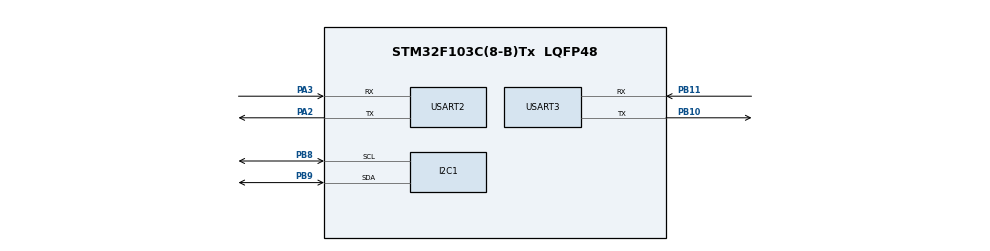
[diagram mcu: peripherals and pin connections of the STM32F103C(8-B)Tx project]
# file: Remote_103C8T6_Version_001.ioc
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Mcu.Family=STM32F1
Mcu.Name=STM32F103C(8-B)Tx
Mcu.Package=LQFP48
NVIC.PriorityGroup=NVIC_PRIORITYGROUP_4
NVIC.USART3_IRQn=true\:0\:0\:false\:false\:true\:true\:true\:true
PA13.Mode=Serial_Wire
PA13.Signal=SYS_JTMS-SWDIO
PA14.Mode=Serial_Wire
PA14.Signal=SYS_JTCK-SWCLK
PA2.Mode=Asynchronous
PA2.Signal=USART2_TX
PA3.Mode=Asynchronous
PA3.Signal=USART2_RX
PB10.Mode=Asynchronous
PB10.Signal=USART3_TX
PB11.Mode=Asynchronous
PB11.Signal=USART3_RX
PB8.Mode=I2C
PB8.Signal=I2C1_SCL
PB9.Mode=I2C
PB9.Signal=I2C1_SDA
PC14-OSC32_IN.Mode=LSE-External-Oscillator
PC14-OSC32_IN.Signal=RCC_OSC32_IN
PC15-OSC32_OUT.Mode=LSE-External-Oscillator
PC15-OSC32_OUT.Signal=RCC_OSC32_OUT
PD0-OSC_IN.Mode=HSE-External-Oscillator
PD0-OSC_IN.Signal=RCC_OSC_IN
PD1-OSC_OUT.Mode=HSE-External-Oscillator
PD1-OSC_OUT.Signal=RCC_OSC_OUT
ProjectManager.HeapSize=0x200
ProjectManager.StackSize=0x400
ProjectManager.TargetToolchain=STM32CubeIDE
RCC.APB1Freq_Value=8000000
RCC.APB2Freq_Value=8000000
USART2.VirtualMode=VM_ASYNC
USART3.VirtualMode=VM_ASYNC
board=custom

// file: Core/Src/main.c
/* USER CODE BEGIN Header */
/**
 ******************************************************************************
 * @file           : main.c
 * @brief          : Main program body
 ******************************************************************************
 * @attention
 *
 * Copyright (c) 2025 STMicroelectronics.
 * All rights reserved.
 *
 * This software is licensed under terms that can be found in the LICENSE file
 * in the root directory of this software component.
 * If no LICENSE file comes with this software, it is provided AS-IS.
 *
 ******************************************************************************
 */
/* USER CODE END Header */
#include "main.h"

/* USER CODE BEGIN Includes */
#include<string.h>
#include<stdio.h>
#include "stm32f1xx_hal.h"
#include "stm32f1xx_hal_gpio_ex.h"
#include "stm32f1xx_hal_rcc_ex.h"
#include <stdint.h>
#include <stdlib.h>
#include"ssd1306.h"

/* USER CODE END Includes */

I2C_HandleTypeDef hi2c1;

UART_HandleTypeDef huart2;
UART_HandleTypeDef huart3;

/* USER CODE BEGIN PV */
#define RBUF_SIZE 256
volatile uint8_t rbuf[RBUF_SIZE];
volatile uint16_t rhead = 0, rtail = 0;

uint8_t rx3_byte;
uint8_t c;
char line[32];
uint8_t idx = 0;
/* USER CODE END PV */

void SystemClock_Config(void);
static void MX_GPIO_Init(void);
static void MX_USART2_UART_Init(void);
static void MX_USART3_UART_Init(void);
static void MX_I2C1_Init(void);

/* USER CODE BEGIN 0 */
static inline void rbuf_push_isr(uint8_t b) {
	uint16_t next = (rhead + 1) & (RBUF_SIZE - 1);
	if (next != rtail) {
		rbuf[rhead] = b;
		rhead = next;
	}
}

/* -------- Pop Byte from Ring Buffer -------- */
static inline int rbuf_pop(uint8_t *out) {
	__disable_irq();
	if (rtail == rhead) {
		__enable_irq();
		return 0;
	}
	*out = rbuf[rtail];
	rtail = (rtail + 1) & (RBUF_SIZE - 1);
	__enable_irq();
	return 1;
}

/* -------- UART RX ISR -------- */
void HAL_UART_RxCpltCallback(UART_HandleTypeDef *huart) {
	if (huart->Instance == USART3) {
		rbuf_push_isr(rx3_byte);
		HAL_UART_Receive_IT(&huart3, &rx3_byte, 1);
	}
}

/* -------- UART error handle -------- */
void HAL_UART_ErrorCallback(UART_HandleTypeDef *huart) {
	if (huart->Instance == USART3) {
		__HAL_UART_CLEAR_OREFLAG(huart);
		HAL_UART_Receive_IT(&huart3, &rx3_byte, 1);
	}
}

void UART3_SendString(char *s) {
	HAL_UART_Transmit(&huart3, (uint8_t*) s, strlen(s), HAL_MAX_DELAY);
}
/* USER CODE END 0 */

int main(void)
{

  /* MCU Configuration--------------------------------------------------------*/

  /* Reset of all peripherals, Initializes the Flash interface and the Systick. */
  HAL_Init();

  /* USER CODE BEGIN Init */
	__HAL_RCC_AFIO_CLK_ENABLE();           // IMPORTANT
	// PB10/PB11 used
  /* USER CODE END Init */

  /* Configure the system clock */
  SystemClock_Config();

  /* Initialize all configured peripherals */
  MX_GPIO_Init();
  MX_USART2_UART_Init();
  MX_USART3_UART_Init();
  MX_I2C1_Init();
  /* USER CODE BEGIN 2 */
	HAL_UART_Receive_IT(&huart3, &rx3_byte, 1);

	/* ---- OLED ---- */
	SSD1306_Init();
	SSD1306_Clear();
	SSD1306_Update();

	/* ---- Start Msg ---- */
	char startMsg[] = "STM32 UART3 Ready\r\n";
	HAL_UART_Transmit(&huart2, (uint8_t*) startMsg, strlen(startMsg),
	HAL_MAX_DELAY);

	uint8_t c;
	static char line[64];
	static uint8_t idx = 0;
  /* USER CODE END 2 */

  /* Infinite loop */
	while (1) {

    /* USER CODE BEGIN 3 */
		while (rbuf_pop(&c)) {

			if (c == '\n') {

				line[idx] = '\0';
				idx = 0;

				/* ---------- Process BTN:x ---------- */
				if (strncmp(line, "BTN:", 4) == 0) {

					int btn = atoi(&line[4]);

					char msg[40];
					sprintf(msg, "Button %d Pressed\r\n", btn);

					/* Send back to ESP32 */
					UART3_SendString(msg);

					/* Print on UART2 (PC) */
					HAL_UART_Transmit(&huart2, (uint8_t*) msg, strlen(msg),
					HAL_MAX_DELAY);

					/* -------- OLED Output -------- */
					SSD1306_Clear();
					SSD1306_WriteStringXY(0, 0, "BUTTON PRESSED:");
					char oledMsg[20];
					sprintf(oledMsg, "%d", btn);
					SSD1306_WriteStringXY(0, 20, oledMsg);
					SSD1306_Update();
				}
			} else if (c != '\r') {
				if (idx < sizeof(line) - 1)
					line[idx++] = c;
			}
		}

		HAL_Delay(1);

	}
  /* USER CODE END 3 */
}

void SystemClock_Config(void)
{
  RCC_OscInitTypeDef RCC_OscInitStruct = {0};
  RCC_ClkInitTypeDef RCC_ClkInitStruct = {0};

  /** Initializes the RCC Oscillators according to the specified parameters
  * in the RCC_OscInitTypeDef structure.
  */
  RCC_OscInitStruct.OscillatorType = RCC_OSCILLATORTYPE_HSE;
  RCC_OscInitStruct.HSEState = RCC_HSE_ON;
  RCC_OscInitStruct.HSEPredivValue = RCC_HSE_PREDIV_DIV1;
  RCC_OscInitStruct.HSIState = RCC_HSI_ON;
  RCC_OscInitStruct.PLL.PLLState = RCC_PLL_ON;
  RCC_OscInitStruct.PLL.PLLSource = RCC_PLLSOURCE_HSE;
  RCC_OscInitStruct.PLL.PLLMUL = RCC_PLL_MUL9;
  if (HAL_RCC_OscConfig(&RCC_OscInitStruct) != HAL_OK)
  {
    Error_Handler();
  }

  /** Initializes the CPU, AHB and APB buses clocks
  */
  RCC_ClkInitStruct.ClockType = RCC_CLOCKTYPE_HCLK|RCC_CLOCKTYPE_SYSCLK
                              |RCC_CLOCKTYPE_PCLK1|RCC_CLOCKTYPE_PCLK2;
  RCC_ClkInitStruct.SYSCLKSource = RCC_SYSCLKSOURCE_PLLCLK;
  RCC_ClkInitStruct.AHBCLKDivider = RCC_SYSCLK_DIV2;
  RCC_ClkInitStruct.APB1CLKDivider = RCC_HCLK_DIV2;
  RCC_ClkInitStruct.APB2CLKDivider = RCC_HCLK_DIV1;

  if (HAL_RCC_ClockConfig(&RCC_ClkInitStruct, FLASH_LATENCY_2) != HAL_OK)
  {
    Error_Handler();
  }
}

static void MX_I2C1_Init(void)
{

  hi2c1.Instance = I2C1;
  hi2c1.Init.ClockSpeed = 100000;
  hi2c1.Init.DutyCycle = I2C_DUTYCYCLE_2;
  hi2c1.Init.OwnAddress1 = 0;
  hi2c1.Init.AddressingMode = I2C_ADDRESSINGMODE_7BIT;
  hi2c1.Init.DualAddressMode = I2C_DUALADDRESS_DISABLE;
  hi2c1.Init.OwnAddress2 = 0;
  hi2c1.Init.GeneralCallMode = I2C_GENERALCALL_DISABLE;
  hi2c1.Init.NoStretchMode = I2C_NOSTRETCH_DISABLE;
  if (HAL_I2C_Init(&hi2c1) != HAL_OK)
  {
    Error_Handler();
  }

}

static void MX_USART2_UART_Init(void)
{

  huart2.Instance = USART2;
  huart2.Init.BaudRate = 115200;
  huart2.Init.WordLength = UART_WORDLENGTH_8B;
  huart2.Init.StopBits = UART_STOPBITS_1;
  huart2.Init.Parity = UART_PARITY_NONE;
  huart2.Init.Mode = UART_MODE_TX_RX;
  huart2.Init.HwFlowCtl = UART_HWCONTROL_NONE;
  huart2.Init.OverSampling = UART_OVERSAMPLING_16;
  if (HAL_UART_Init(&huart2) != HAL_OK)
  {
    Error_Handler();
  }

}

static void MX_USART3_UART_Init(void)
{

  huart3.Instance = USART3;
  huart3.Init.BaudRate = 115200;
  huart3.Init.WordLength = UART_WORDLENGTH_8B;
  huart3.Init.StopBits = UART_STOPBITS_1;
  huart3.Init.Parity = UART_PARITY_NONE;
  huart3.Init.Mode = UART_MODE_TX_RX;
  huart3.Init.HwFlowCtl = UART_HWCONTROL_NONE;
  huart3.Init.OverSampling = UART_OVERSAMPLING_16;
  if (HAL_UART_Init(&huart3) != HAL_OK)
  {
    Error_Handler();
  }

}

static void MX_GPIO_Init(void)
{

  /* GPIO Ports Clock Enable */
  __HAL_RCC_GPIOC_CLK_ENABLE();
  __HAL_RCC_GPIOD_CLK_ENABLE();
  __HAL_RCC_GPIOA_CLK_ENABLE();
  __HAL_RCC_GPIOB_CLK_ENABLE();

}

void Error_Handler(void)
{
	__disable_irq();
	while (1) {
	}
}
